One B-rep face of a CAD part: STEP entity #629.
In plain terms, the cylindrical face has radius 38 mm (diameter 76 mm), a partial arc.
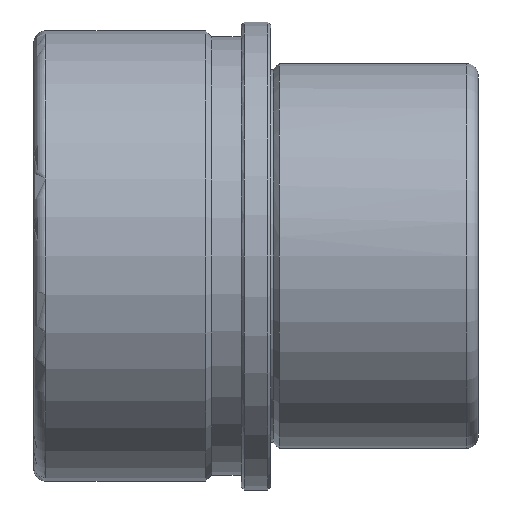
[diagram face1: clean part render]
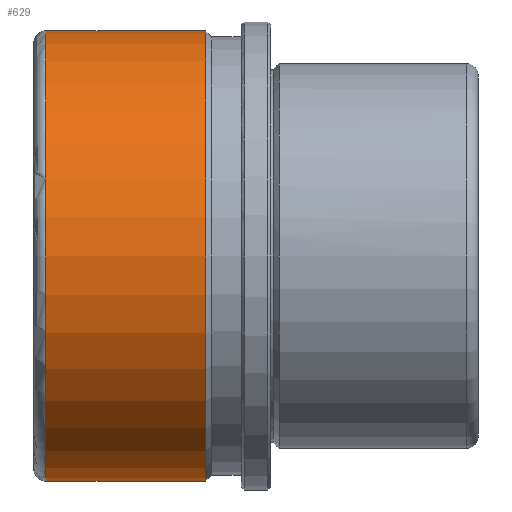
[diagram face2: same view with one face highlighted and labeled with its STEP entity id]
Its self-contained STEP definition (entity closure, numbers rounded to 3 decimals):
#414=CARTESIAN_POINT('Line Origine',(35.,0.,38.)) ;
#418=CARTESIAN_POINT('Vertex',(-11.,0.,38.)) ;
#420=CARTESIAN_POINT('Vertex',(-38.,0.,38.)) ;
#434=CARTESIAN_POINT('Vertex',(-11.,0.,-38.)) ;
#437=CARTESIAN_POINT('Line Origine',(35.,0.,-38.)) ;
#441=CARTESIAN_POINT('Vertex',(-38.,0.,-38.)) ;
#592=CARTESIAN_POINT('Axis2P3D Location',(35.,0.,0.)) ;
#597=CARTESIAN_POINT('Axis2P3D Location',(-11.,0.,0.)) ;
#601=CARTESIAN_POINT('Vertex',(-11.,-38.,0.)) ;
#604=CARTESIAN_POINT('Axis2P3D Location',(-11.,0.,0.)) ;
#609=CARTESIAN_POINT('Axis2P3D Location',(-38.,0.,0.)) ;
#613=CARTESIAN_POINT('Vertex',(-38.,-38.,0.)) ;
#616=CARTESIAN_POINT('Axis2P3D Location',(-38.,0.,0.)) ;
#415=DIRECTION('Vector Direction',(-1.,0.,0.)) ;
#438=DIRECTION('Vector Direction',(-1.,0.,0.)) ;
#593=DIRECTION('Axis2P3D Direction',(-1.,-0.,-0.)) ;
#594=DIRECTION('Axis2P3D XDirection',(0.,0.,-1.)) ;
#598=DIRECTION('Axis2P3D Direction',(-1.,-0.,-0.)) ;
#605=DIRECTION('Axis2P3D Direction',(-1.,-0.,-0.)) ;
#610=DIRECTION('Axis2P3D Direction',(-1.,-0.,-0.)) ;
#617=DIRECTION('Axis2P3D Direction',(-1.,-0.,-0.)) ;
#595=AXIS2_PLACEMENT_3D('Cylinder Axis2P3D',#592,#593,#594) ;
#599=AXIS2_PLACEMENT_3D('Circle Axis2P3D',#597,#598,$) ;
#606=AXIS2_PLACEMENT_3D('Circle Axis2P3D',#604,#605,$) ;
#611=AXIS2_PLACEMENT_3D('Circle Axis2P3D',#609,#610,$) ;
#618=AXIS2_PLACEMENT_3D('Circle Axis2P3D',#616,#617,$) ;
#622=ORIENTED_EDGE('',*,*,#443,.T.) ;
#623=ORIENTED_EDGE('',*,*,#603,.F.) ;
#624=ORIENTED_EDGE('',*,*,#608,.F.) ;
#625=ORIENTED_EDGE('',*,*,#422,.T.) ;
#626=ORIENTED_EDGE('',*,*,#615,.T.) ;
#627=ORIENTED_EDGE('',*,*,#620,.T.) ;
#416=VECTOR('Line Direction',#415,1.) ;
#439=VECTOR('Line Direction',#438,1.) ;
#629=ADVANCED_FACE('CF 641 50 x 75',(#628),#596,.T.) ;
#600=CIRCLE('generated circle',#599,38.) ;
#607=CIRCLE('generated circle',#606,38.) ;
#612=CIRCLE('generated circle',#611,38.) ;
#619=CIRCLE('generated circle',#618,38.) ;
#596=CYLINDRICAL_SURFACE('generated cylinder',#595,38.) ;
#422=EDGE_CURVE('',#419,#421,#417,.T.) ;
#443=EDGE_CURVE('',#442,#435,#440,.F.) ;
#603=EDGE_CURVE('',#602,#435,#600,.F.) ;
#608=EDGE_CURVE('',#419,#602,#607,.F.) ;
#615=EDGE_CURVE('',#421,#614,#612,.F.) ;
#620=EDGE_CURVE('',#614,#442,#619,.F.) ;
#621=EDGE_LOOP('',(#622,#623,#624,#625,#626,#627)) ;
#628=FACE_OUTER_BOUND('',#621,.T.) ;
#417=LINE('Line',#414,#416) ;
#440=LINE('Line',#437,#439) ;
#419=VERTEX_POINT('',#418) ;
#421=VERTEX_POINT('',#420) ;
#435=VERTEX_POINT('',#434) ;
#442=VERTEX_POINT('',#441) ;
#602=VERTEX_POINT('',#601) ;
#614=VERTEX_POINT('',#613) ;
